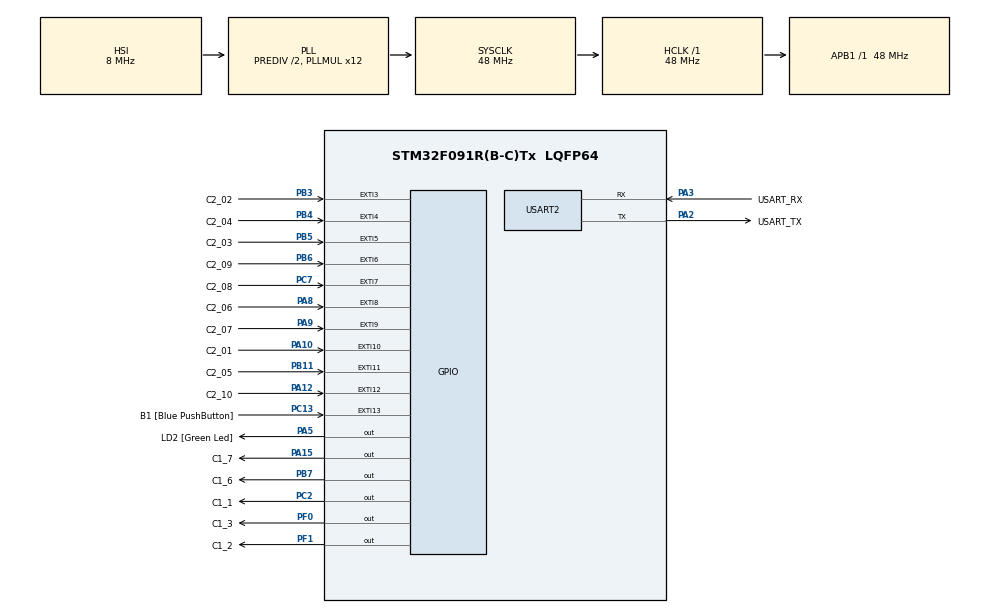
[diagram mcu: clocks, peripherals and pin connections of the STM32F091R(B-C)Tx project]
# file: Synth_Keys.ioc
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Mcu.Family=STM32F0
Mcu.Name=STM32F091R(B-C)Tx
Mcu.Package=LQFP64
NVIC.EXTI2_3_IRQn=true\:0\:0\:false\:false\:true\:true\:true
NVIC.EXTI4_15_IRQn=true\:0\:0\:false\:false\:true\:true\:true
PA10.GPIO_Label=C2_01
PA10.GPIO_PuPd=GPIO_PULLDOWN
PA10.Signal=GPXTI10
PA12.GPIO_Label=C2_10
PA12.GPIO_PuPd=GPIO_PULLDOWN
PA12.Signal=GPXTI12
PA13.GPIO_Label=TMS
PA13.Mode=Serial_Wire
PA13.Signal=SYS_SWDIO
PA14.GPIO_Label=TCK
PA14.Mode=Serial_Wire
PA14.Signal=SYS_SWCLK
PA15.GPIO_Label=C1_7
PA15.Signal=GPIO_Output
PA2.GPIO_Label=USART_TX
PA2.GPIO_Mode=GPIO_MODE_AF_PP
PA2.GPIO_PuPd=GPIO_NOPULL
PA2.GPIO_Speed=GPIO_SPEED_FREQ_LOW
PA2.Mode=Asynchronous
PA2.Signal=USART2_TX
PA3.GPIO_Label=USART_RX
PA3.GPIO_Mode=GPIO_MODE_AF_PP
PA3.GPIO_PuPd=GPIO_NOPULL
PA3.GPIO_Speed=GPIO_SPEED_FREQ_LOW
PA3.Mode=Asynchronous
PA3.Signal=USART2_RX
PA5.GPIO_Label=LD2 [Green Led]
PA5.GPIO_Mode=GPIO_MODE_OUTPUT_PP
PA5.GPIO_PuPd=GPIO_NOPULL
PA5.GPIO_Speed=GPIO_SPEED_FREQ_LOW
PA5.Signal=GPIO_Output
PA8.GPIO_Label=C2_06
PA8.GPIO_PuPd=GPIO_PULLDOWN
PA8.Signal=GPXTI8
PA9.GPIO_Label=C2_07
PA9.GPIO_PuPd=GPIO_PULLDOWN
PA9.Signal=GPXTI9
PB11.GPIO_Label=C2_05
PB11.GPIO_PuPd=GPIO_PULLDOWN
PB11.Signal=GPXTI11
PB3.GPIO_Label=C2_02
PB3.GPIO_PuPd=GPIO_PULLDOWN
PB3.Signal=GPXTI3
PB4.GPIO_Label=C2_04
PB4.GPIO_PuPd=GPIO_PULLDOWN
PB4.Signal=GPXTI4
PB5.GPIO_Label=C2_03
PB5.GPIO_PuPd=GPIO_PULLDOWN
PB5.Signal=GPXTI5
PB6.GPIO_Label=C2_09
PB6.GPIO_PuPd=GPIO_PULLDOWN
PB6.Signal=GPXTI6
PB7.GPIO_Label=C1_6
PB7.Signal=GPIO_Output
PC13.GPIO_Label=B1 [Blue PushButton]
PC13.GPIO_ModeDefaultEXTI=GPIO_MODE_IT_FALLING
PC13.Signal=GPXTI13
PC14OSC32_IN.GPIO_Label=C1_5
PC14OSC32_IN.Signal=GPIO_Output
PC15OSC32_OUT.GPIO_Label=C1_4
PC15OSC32_OUT.Signal=GPIO_Output
PC2.GPIO_Label=C1_1
PC2.Signal=GPIO_Output
PC7.GPIO_Label=C2_08
PC7.GPIO_PuPd=GPIO_PULLDOWN
PC7.Signal=GPXTI7
PF0-OSC_IN.GPIO_Label=C1_3
PF0-OSC_IN.Signal=GPIO_Output
PF1-OSC_OUT.GPIO_Label=C1_2
PF1-OSC_OUT.Signal=GPIO_Output
ProjectManager.HeapSize=0x200
ProjectManager.StackSize=0x400
ProjectManager.TargetToolchain=TrueSTUDIO
RCC.AHBFreq_Value=48000000
RCC.APB1Freq_Value=48000000
RCC.APB1TimFreq_Value=48000000
RCC.FLatency-AdvancedSettings=FLASH_LATENCY_1
RCC.HCLKFreq_Value=48000000
RCC.PLLDivider=RCC_PREDIV_DIV2
RCC.PLLMUL=RCC_PLL_MUL12
RCC.PREFETCH_ENABLE-AdvancedSettings=1
RCC.SYSCLKFreq_VALUE=48000000
RCC.SYSCLKSource=RCC_SYSCLKSOURCE_PLLCLK
USART2.VirtualMode=VM_ASYNC
USART2.VirtualMode-Asynchronous=VM_ASYNC
board=NUCLEO-F091RC

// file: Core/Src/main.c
/* USER CODE BEGIN Header */
/**
  ******************************************************************************
  * @file           : main.c
  * @brief          : Main program body
  ******************************************************************************
  * @attention
  *
  * <h2><center>&copy; Copyright (c) 2021 STMicroelectronics.
  * All rights reserved.</center></h2>
  *
  * This software component is licensed by ST under BSD 3-Clause license,
  * the "License"; You may not use this file except in compliance with the
  * License. You may obtain a copy of the License at:
  *                        opensource.org/licenses/BSD-3-Clause
  *
  ******************************************************************************
  */
/* USER CODE END Header */
#include "main.h"

UART_HandleTypeDef huart2;

/* USER CODE BEGIN PV */
uint8_t scanLine = 1;
uint16_t currentKey = -1;
/* USER CODE END PV */

void SystemClock_Config(void);
static void MX_GPIO_Init(void);
static void MX_USART2_UART_Init(void);

int main(void)
{

  /* MCU Configuration--------------------------------------------------------*/

  /* Reset of all peripherals, Initializes the Flash interface and the Systick. */
  HAL_Init();

  /* Configure the system clock */
  SystemClock_Config();

  /* Initialize all configured peripherals */
  MX_GPIO_Init();
  MX_USART2_UART_Init();

  /* Infinite loop */
  while (1)
  {
	  switch(currentKey)
	  {
	  	  case C2_01_Pin:
	  		  HAL_GPIO_WritePin(LD2_GPIO_Port, LD2_Pin, GPIO_PIN_SET);
	  		  break;
	  	  case C2_02_Pin:
	  		  		  HAL_GPIO_WritePin(LD2_GPIO_Port, LD2_Pin, GPIO_PIN_SET);
	  		  		  break;
	  	  case C2_03_Pin:
	  		  		  HAL_GPIO_WritePin(LD2_GPIO_Port, LD2_Pin, GPIO_PIN_SET);
	  		  		  break;
	  	  case C2_04_Pin:
	  		  		  HAL_GPIO_WritePin(LD2_GPIO_Port, LD2_Pin, GPIO_PIN_SET);
	  		  		  break;
	  	  case C2_05_Pin:
	  		  		  HAL_GPIO_WritePin(LD2_GPIO_Port, LD2_Pin, GPIO_PIN_SET);
	  		  		  break;
	  	  case C2_06_Pin:
	  		  		  HAL_GPIO_WritePin(LD2_GPIO_Port, LD2_Pin, GPIO_PIN_SET);
	  		  		  break;
	  	  case C2_07_Pin:
	  		  		  HAL_GPIO_WritePin(LD2_GPIO_Port, LD2_Pin, GPIO_PIN_SET);
	  		  		  break;
	  	  case C2_08_Pin:
	  		  		  HAL_GPIO_WritePin(LD2_GPIO_Port, LD2_Pin, GPIO_PIN_SET);
	  		  		  break;
	  	  case C2_09_Pin:
	  		  		  HAL_GPIO_WritePin(LD2_GPIO_Port, LD2_Pin, GPIO_PIN_SET);
	  		  		  break;
	  	  case C2_10_Pin:
	  		  		  HAL_GPIO_WritePin(LD2_GPIO_Port, LD2_Pin, GPIO_PIN_SET);
	  		  		  break;
	  }
  }
}

void SystemClock_Config(void)
{
  RCC_OscInitTypeDef RCC_OscInitStruct = {0};
  RCC_ClkInitTypeDef RCC_ClkInitStruct = {0};
  RCC_PeriphCLKInitTypeDef PeriphClkInit = {0};

  /** Initializes the RCC Oscillators according to the specified parameters
  * in the RCC_OscInitTypeDef structure.
  */
  RCC_OscInitStruct.OscillatorType = RCC_OSCILLATORTYPE_HSI;
  RCC_OscInitStruct.HSIState = RCC_HSI_ON;
  RCC_OscInitStruct.HSICalibrationValue = RCC_HSICALIBRATION_DEFAULT;
  RCC_OscInitStruct.PLL.PLLState = RCC_PLL_ON;
  RCC_OscInitStruct.PLL.PLLSource = RCC_PLLSOURCE_HSI;
  RCC_OscInitStruct.PLL.PLLMUL = RCC_PLL_MUL12;
  RCC_OscInitStruct.PLL.PREDIV = RCC_PREDIV_DIV2;
  if (HAL_RCC_OscConfig(&RCC_OscInitStruct) != HAL_OK)
  {
    Error_Handler();
  }
  /** Initializes the CPU, AHB and APB buses clocks
  */
  RCC_ClkInitStruct.ClockType = RCC_CLOCKTYPE_HCLK|RCC_CLOCKTYPE_SYSCLK
                              |RCC_CLOCKTYPE_PCLK1;
  RCC_ClkInitStruct.SYSCLKSource = RCC_SYSCLKSOURCE_PLLCLK;
  RCC_ClkInitStruct.AHBCLKDivider = RCC_SYSCLK_DIV1;
  RCC_ClkInitStruct.APB1CLKDivider = RCC_HCLK_DIV1;

  if (HAL_RCC_ClockConfig(&RCC_ClkInitStruct, FLASH_LATENCY_1) != HAL_OK)
  {
    Error_Handler();
  }
  PeriphClkInit.PeriphClockSelection = RCC_PERIPHCLK_USART2;
  PeriphClkInit.Usart2ClockSelection = RCC_USART2CLKSOURCE_PCLK1;
  if (HAL_RCCEx_PeriphCLKConfig(&PeriphClkInit) != HAL_OK)
  {
    Error_Handler();
  }
}

static void MX_USART2_UART_Init(void)
{

  huart2.Instance = USART2;
  huart2.Init.BaudRate = 115200;
  huart2.Init.WordLength = UART_WORDLENGTH_8B;
  huart2.Init.StopBits = UART_STOPBITS_1;
  huart2.Init.Parity = UART_PARITY_NONE;
  huart2.Init.Mode = UART_MODE_TX_RX;
  huart2.Init.HwFlowCtl = UART_HWCONTROL_NONE;
  huart2.Init.OverSampling = UART_OVERSAMPLING_16;
  huart2.Init.OneBitSampling = UART_ONE_BIT_SAMPLE_DISABLE;
  huart2.AdvancedInit.AdvFeatureInit = UART_ADVFEATURE_NO_INIT;
  if (HAL_UART_Init(&huart2) != HAL_OK)
  {
    Error_Handler();
  }

}

static void MX_GPIO_Init(void)
{
  GPIO_InitTypeDef GPIO_InitStruct = {0};

  /* GPIO Ports Clock Enable */
  __HAL_RCC_GPIOC_CLK_ENABLE();
  __HAL_RCC_GPIOF_CLK_ENABLE();
  __HAL_RCC_GPIOA_CLK_ENABLE();
  __HAL_RCC_GPIOB_CLK_ENABLE();

  /*Configure GPIO pin Output Level */
  HAL_GPIO_WritePin(GPIOC, C1_5_Pin|C1_4_Pin|C1_1_Pin, GPIO_PIN_RESET);

  /*Configure GPIO pin Output Level */
  HAL_GPIO_WritePin(GPIOF, C1_3_Pin|C1_2_Pin, GPIO_PIN_RESET);

  /*Configure GPIO pin Output Level */
  HAL_GPIO_WritePin(GPIOA, LD2_Pin|C1_7_Pin, GPIO_PIN_RESET);

  /*Configure GPIO pin Output Level */
  HAL_GPIO_WritePin(C1_6_GPIO_Port, C1_6_Pin, GPIO_PIN_RESET);

  /*Configure GPIO pin : B1_Pin */
  GPIO_InitStruct.Pin = B1_Pin;
  GPIO_InitStruct.Mode = GPIO_MODE_IT_FALLING;
  GPIO_InitStruct.Pull = GPIO_NOPULL;
  HAL_GPIO_Init(B1_GPIO_Port, &GPIO_InitStruct);

  /*Configure GPIO pins : C1_5_Pin C1_4_Pin C1_1_Pin */
  GPIO_InitStruct.Pin = C1_5_Pin|C1_4_Pin|C1_1_Pin;
  GPIO_InitStruct.Mode = GPIO_MODE_OUTPUT_PP;
  GPIO_InitStruct.Pull = GPIO_NOPULL;
  GPIO_InitStruct.Speed = GPIO_SPEED_FREQ_LOW;
  HAL_GPIO_Init(GPIOC, &GPIO_InitStruct);

  /*Configure GPIO pins : C1_3_Pin C1_2_Pin */
  GPIO_InitStruct.Pin = C1_3_Pin|C1_2_Pin;
  GPIO_InitStruct.Mode = GPIO_MODE_OUTPUT_PP;
  GPIO_InitStruct.Pull = GPIO_NOPULL;
  GPIO_InitStruct.Speed = GPIO_SPEED_FREQ_LOW;
  HAL_GPIO_Init(GPIOF, &GPIO_InitStruct);

  /*Configure GPIO pins : LD2_Pin C1_7_Pin */
  GPIO_InitStruct.Pin = LD2_Pin|C1_7_Pin;
  GPIO_InitStruct.Mode = GPIO_MODE_OUTPUT_PP;
  GPIO_InitStruct.Pull = GPIO_NOPULL;
  GPIO_InitStruct.Speed = GPIO_SPEED_FREQ_LOW;
  HAL_GPIO_Init(GPIOA, &GPIO_InitStruct);

  /*Configure GPIO pins : C2_05_Pin C2_02_Pin C2_04_Pin C2_03_Pin
                           C2_09_Pin */
  GPIO_InitStruct.Pin = C2_05_Pin|C2_02_Pin|C2_04_Pin|C2_03_Pin
                          |C2_09_Pin;
  GPIO_InitStruct.Mode = GPIO_MODE_IT_RISING;
  GPIO_InitStruct.Pull = GPIO_PULLDOWN;
  HAL_GPIO_Init(GPIOB, &GPIO_InitStruct);

  /*Configure GPIO pin : C2_08_Pin */
  GPIO_InitStruct.Pin = C2_08_Pin;
  GPIO_InitStruct.Mode = GPIO_MODE_IT_RISING;
  GPIO_InitStruct.Pull = GPIO_PULLDOWN;
  HAL_GPIO_Init(C2_08_GPIO_Port, &GPIO_InitStruct);

  /*Configure GPIO pins : C2_06_Pin C2_07_Pin C2_01_Pin C2_10_Pin */
  GPIO_InitStruct.Pin = C2_06_Pin|C2_07_Pin|C2_01_Pin|C2_10_Pin;
  GPIO_InitStruct.Mode = GPIO_MODE_IT_RISING;
  GPIO_InitStruct.Pull = GPIO_PULLDOWN;
  HAL_GPIO_Init(GPIOA, &GPIO_InitStruct);

  /*Configure GPIO pin : C1_6_Pin */
  GPIO_InitStruct.Pin = C1_6_Pin;
  GPIO_InitStruct.Mode = GPIO_MODE_OUTPUT_PP;
  GPIO_InitStruct.Pull = GPIO_NOPULL;
  GPIO_InitStruct.Speed = GPIO_SPEED_FREQ_LOW;
  HAL_GPIO_Init(C1_6_GPIO_Port, &GPIO_InitStruct);

  /* EXTI interrupt init*/
  HAL_NVIC_SetPriority(EXTI2_3_IRQn, 0, 0);
  HAL_NVIC_EnableIRQ(EXTI2_3_IRQn);

  HAL_NVIC_SetPriority(EXTI4_15_IRQn, 0, 0);
  HAL_NVIC_EnableIRQ(EXTI4_15_IRQn);

}

/* USER CODE BEGIN 4 */
void HAL_GPIO_EXTI_Callback(uint16_t GPIO_Pin)
{
	currentKey = GPIO_Pin;
}
/* USER CODE END 4 */

void Error_Handler(void)
{
  __disable_irq();
  while (1)
  {
  }
}

/************************ (C) COPYRIGHT STMicroelectronics *****END OF FILE****/
